VERSION 5.7 ;
  NOWIREEXTENSIONATPIN ON ;
  DIVIDERCHAR "/" ;
  BUSBITCHARS "[]" ;
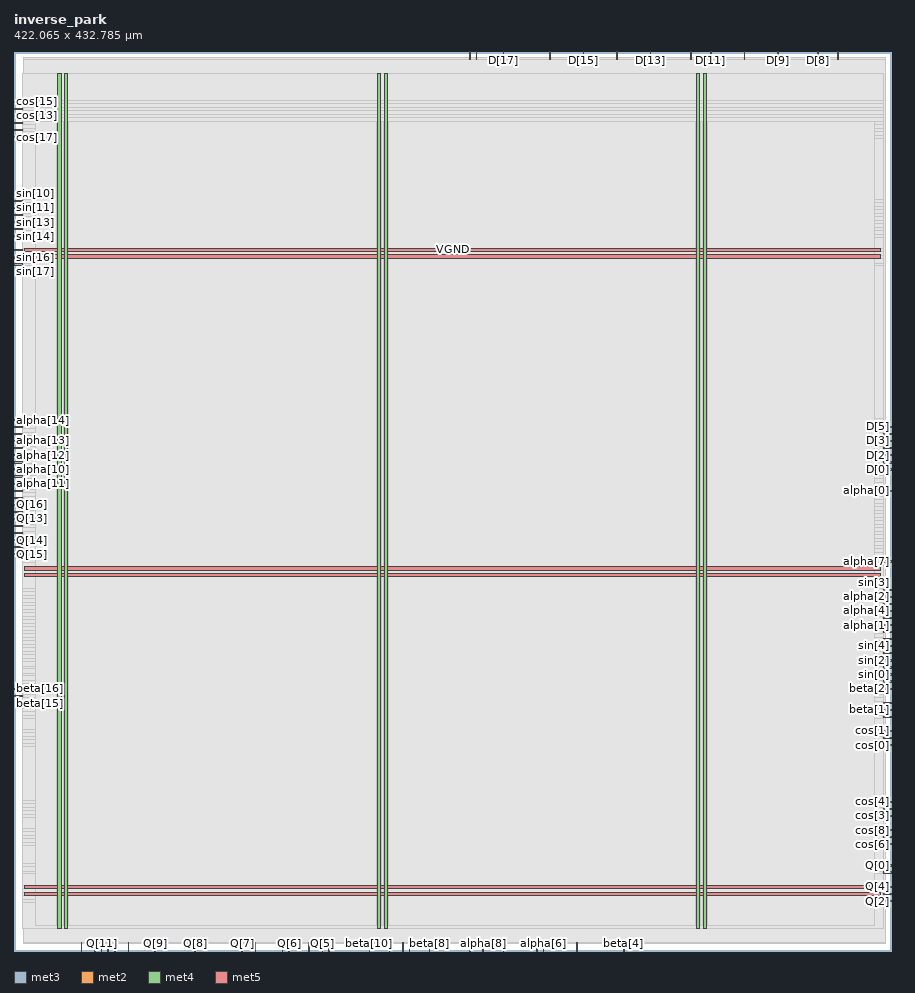
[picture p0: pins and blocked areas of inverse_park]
MACRO inverse_park
  CLASS BLOCK ;
  FOREIGN inverse_park ;
  ORIGIN 0.000 0.000 ;
  SIZE 422.065 BY 432.785 ;
  PIN D[0]
    DIRECTION INPUT ;
    USE SIGNAL ;
    ANTENNAGATEAREA 0.196500 ;
    PORT
      LAYER met3 ;
        RECT 418.065 231.240 422.065 231.840 ;
    END
  END D[0]
  PIN D[10]
    DIRECTION INPUT ;
    USE SIGNAL ;
    ANTENNAGATEAREA 0.213000 ;
    PORT
      LAYER met2 ;
        RECT 351.070 428.785 351.350 432.785 ;
    END
  END D[10]
  PIN D[11]
    DIRECTION INPUT ;
    USE SIGNAL ;
    ANTENNAGATEAREA 0.196500 ;
    PORT
      LAYER met2 ;
        RECT 334.970 428.785 335.250 432.785 ;
    END
  END D[11]
  PIN D[12]
    DIRECTION INPUT ;
    USE SIGNAL ;
    ANTENNAGATEAREA 0.196500 ;
    PORT
      LAYER met2 ;
        RECT 325.310 428.785 325.590 432.785 ;
    END
  END D[12]
  PIN D[13]
    DIRECTION INPUT ;
    USE SIGNAL ;
    ANTENNAGATEAREA 0.196500 ;
    PORT
      LAYER met2 ;
        RECT 305.990 428.785 306.270 432.785 ;
    END
  END D[13]
  PIN D[14]
    DIRECTION INPUT ;
    USE SIGNAL ;
    ANTENNAGATEAREA 0.159000 ;
    PORT
      LAYER met2 ;
        RECT 289.890 428.785 290.170 432.785 ;
    END
  END D[14]
  PIN D[15]
    DIRECTION INPUT ;
    USE SIGNAL ;
    ANTENNAGATEAREA 0.196500 ;
    PORT
      LAYER met2 ;
        RECT 273.790 428.785 274.070 432.785 ;
    END
  END D[15]
  PIN D[16]
    DIRECTION INPUT ;
    USE SIGNAL ;
    ANTENNAGATEAREA 0.196500 ;
    PORT
      LAYER met2 ;
        RECT 257.690 428.785 257.970 432.785 ;
    END
  END D[16]
  PIN D[17]
    DIRECTION INPUT ;
    USE SIGNAL ;
    ANTENNAGATEAREA 0.213000 ;
    PORT
      LAYER met2 ;
        RECT 235.150 428.785 235.430 432.785 ;
    END
  END D[17]
  PIN D[18]
    DIRECTION INPUT ;
    USE SIGNAL ;
    ANTENNAGATEAREA 0.159000 ;
    PORT
      LAYER met2 ;
        RECT 219.050 428.785 219.330 432.785 ;
    END
  END D[18]
  PIN D[1]
    DIRECTION INPUT ;
    USE SIGNAL ;
    ANTENNAGATEAREA 0.159000 ;
    PORT
      LAYER met3 ;
        RECT 418.065 234.640 422.065 235.240 ;
    END
  END D[1]
  PIN D[2]
    DIRECTION INPUT ;
    USE SIGNAL ;
    ANTENNAGATEAREA 0.213000 ;
    PORT
      LAYER met3 ;
        RECT 418.065 238.040 422.065 238.640 ;
    END
  END D[2]
  PIN D[3]
    DIRECTION INPUT ;
    USE SIGNAL ;
    ANTENNAGATEAREA 0.159000 ;
    PORT
      LAYER met3 ;
        RECT 418.065 241.440 422.065 242.040 ;
    END
  END D[3]
  PIN D[4]
    DIRECTION INPUT ;
    USE SIGNAL ;
    ANTENNAGATEAREA 0.196500 ;
    PORT
      LAYER met3 ;
        RECT 418.065 244.840 422.065 245.440 ;
    END
  END D[4]
  PIN D[5]
    DIRECTION INPUT ;
    USE SIGNAL ;
    ANTENNAGATEAREA 0.213000 ;
    PORT
      LAYER met3 ;
        RECT 418.065 248.240 422.065 248.840 ;
    END
  END D[5]
  PIN D[6]
    DIRECTION INPUT ;
    USE SIGNAL ;
    ANTENNAGATEAREA 0.196500 ;
    PORT
      LAYER met3 ;
        RECT 418.065 251.640 422.065 252.240 ;
    END
  END D[6]
  PIN D[7]
    DIRECTION INPUT ;
    USE SIGNAL ;
    ANTENNAGATEAREA 0.159000 ;
    PORT
      LAYER met2 ;
        RECT 396.150 428.785 396.430 432.785 ;
    END
  END D[7]
  PIN D[8]
    DIRECTION INPUT ;
    USE SIGNAL ;
    ANTENNAGATEAREA 0.196500 ;
    PORT
      LAYER met2 ;
        RECT 386.490 428.785 386.770 432.785 ;
    END
  END D[8]
  PIN D[9]
    DIRECTION INPUT ;
    USE SIGNAL ;
    ANTENNAGATEAREA 0.213000 ;
    PORT
      LAYER met2 ;
        RECT 367.170 428.785 367.450 432.785 ;
    END
  END D[9]
  PIN Q[0]
    DIRECTION INPUT ;
    USE SIGNAL ;
    ANTENNAGATEAREA 0.213000 ;
    PORT
      LAYER met3 ;
        RECT 418.065 40.840 422.065 41.440 ;
    END
  END Q[0]
  PIN Q[10]
    DIRECTION INPUT ;
    USE SIGNAL ;
    ANTENNAGATEAREA 0.213000 ;
    PORT
      LAYER met2 ;
        RECT 54.830 0.000 55.110 4.000 ;
    END
  END Q[10]
  PIN Q[11]
    DIRECTION INPUT ;
    USE SIGNAL ;
    ANTENNAGATEAREA 0.196500 ;
    PORT
      LAYER met2 ;
        RECT 41.950 0.000 42.230 4.000 ;
    END
  END Q[11]
  PIN Q[12]
    DIRECTION INPUT ;
    USE SIGNAL ;
    ANTENNAGATEAREA 0.196500 ;
    PORT
      LAYER met2 ;
        RECT 32.290 0.000 32.570 4.000 ;
    END
  END Q[12]
  PIN Q[13]
    DIRECTION INPUT ;
    USE SIGNAL ;
    ANTENNAGATEAREA 0.196500 ;
    PORT
      LAYER met3 ;
        RECT 0.000 207.440 4.000 208.040 ;
    END
  END Q[13]
  PIN Q[14]
    DIRECTION INPUT ;
    USE SIGNAL ;
    ANTENNAGATEAREA 0.247500 ;
    PORT
      LAYER met3 ;
        RECT 0.000 197.240 4.000 197.840 ;
    END
  END Q[14]
  PIN Q[15]
    DIRECTION INPUT ;
    USE SIGNAL ;
    ANTENNAGATEAREA 0.495000 ;
    PORT
      LAYER met3 ;
        RECT 0.000 193.840 4.000 194.440 ;
    END
  END Q[15]
  PIN Q[16]
    DIRECTION INPUT ;
    USE SIGNAL ;
    ANTENNAGATEAREA 0.495000 ;
    PORT
      LAYER met3 ;
        RECT 0.000 210.840 4.000 211.440 ;
    END
  END Q[16]
  PIN Q[17]
    DIRECTION INPUT ;
    USE SIGNAL ;
    ANTENNAGATEAREA 0.196500 ;
    PORT
      LAYER met3 ;
        RECT 0.000 200.640 4.000 201.240 ;
    END
  END Q[17]
  PIN Q[18]
    DIRECTION INPUT ;
    USE SIGNAL ;
    ANTENNAGATEAREA 0.196500 ;
    PORT
      LAYER met3 ;
        RECT 0.000 214.240 4.000 214.840 ;
    END
  END Q[18]
  PIN Q[1]
    DIRECTION INPUT ;
    USE SIGNAL ;
    ANTENNAGATEAREA 0.196500 ;
    PORT
      LAYER met3 ;
        RECT 418.065 37.440 422.065 38.040 ;
    END
  END Q[1]
  PIN Q[2]
    DIRECTION INPUT ;
    USE SIGNAL ;
    ANTENNAGATEAREA 0.159000 ;
    PORT
      LAYER met3 ;
        RECT 418.065 27.240 422.065 27.840 ;
    END
  END Q[2]
  PIN Q[3]
    DIRECTION INPUT ;
    USE SIGNAL ;
    ANTENNAGATEAREA 0.213000 ;
    PORT
      LAYER met3 ;
        RECT 418.065 23.840 422.065 24.440 ;
    END
  END Q[3]
  PIN Q[4]
    DIRECTION INPUT ;
    USE SIGNAL ;
    ANTENNAGATEAREA 0.196500 ;
    PORT
      LAYER met3 ;
        RECT 418.065 30.640 422.065 31.240 ;
    END
  END Q[4]
  PIN Q[5]
    DIRECTION INPUT ;
    USE SIGNAL ;
    ANTENNAGATEAREA 0.196500 ;
    PORT
      LAYER met2 ;
        RECT 148.210 0.000 148.490 4.000 ;
    END
  END Q[5]
  PIN Q[6]
    DIRECTION INPUT ;
    USE SIGNAL ;
    ANTENNAGATEAREA 0.196500 ;
    PORT
      LAYER met2 ;
        RECT 132.110 0.000 132.390 4.000 ;
    END
  END Q[6]
  PIN Q[7]
    DIRECTION INPUT ;
    USE SIGNAL ;
    ANTENNAGATEAREA 0.159000 ;
    PORT
      LAYER met2 ;
        RECT 109.570 0.000 109.850 4.000 ;
    END
  END Q[7]
  PIN Q[8]
    DIRECTION INPUT ;
    USE SIGNAL ;
    ANTENNAGATEAREA 0.196500 ;
    PORT
      LAYER met2 ;
        RECT 87.030 0.000 87.310 4.000 ;
    END
  END Q[8]
  PIN Q[9]
    DIRECTION INPUT ;
    USE SIGNAL ;
    ANTENNAGATEAREA 0.213000 ;
    PORT
      LAYER met2 ;
        RECT 67.710 0.000 67.990 4.000 ;
    END
  END Q[9]
  PIN VGND
    DIRECTION INOUT ;
    USE GROUND ;
    PORT
      LAYER met4 ;
        RECT 24.340 10.640 25.940 421.840 ;
    END
    PORT
      LAYER met4 ;
        RECT 177.940 10.640 179.540 421.840 ;
    END
    PORT
      LAYER met4 ;
        RECT 331.540 10.640 333.140 421.840 ;
    END
    PORT
      LAYER met5 ;
        RECT 5.280 30.030 416.540 31.630 ;
    END
    PORT
      LAYER met5 ;
        RECT 5.280 183.210 416.540 184.810 ;
    END
    PORT
      LAYER met5 ;
        RECT 5.280 336.390 416.540 337.990 ;
    END
  END VGND
  PIN VPWR
    DIRECTION INOUT ;
    USE POWER ;
    PORT
      LAYER met4 ;
        RECT 21.040 10.640 22.640 421.840 ;
    END
    PORT
      LAYER met4 ;
        RECT 174.640 10.640 176.240 421.840 ;
    END
    PORT
      LAYER met4 ;
        RECT 328.240 10.640 329.840 421.840 ;
    END
    PORT
      LAYER met5 ;
        RECT 5.280 26.730 416.540 28.330 ;
    END
    PORT
      LAYER met5 ;
        RECT 5.280 179.910 416.540 181.510 ;
    END
    PORT
      LAYER met5 ;
        RECT 5.280 333.090 416.540 334.690 ;
    END
  END VPWR
  PIN alpha[0]
    DIRECTION OUTPUT ;
    USE SIGNAL ;
    ANTENNADIFFAREA 0.445500 ;
    PORT
      LAYER met3 ;
        RECT 418.065 221.040 422.065 221.640 ;
    END
  END alpha[0]
  PIN alpha[10]
    DIRECTION OUTPUT ;
    USE SIGNAL ;
    ANTENNADIFFAREA 0.795200 ;
    PORT
      LAYER met3 ;
        RECT 0.000 231.240 4.000 231.840 ;
    END
  END alpha[10]
  PIN alpha[11]
    DIRECTION OUTPUT ;
    USE SIGNAL ;
    ANTENNADIFFAREA 0.795200 ;
    PORT
      LAYER met3 ;
        RECT 0.000 227.840 4.000 228.440 ;
    END
  END alpha[11]
  PIN alpha[12]
    DIRECTION OUTPUT ;
    USE SIGNAL ;
    ANTENNADIFFAREA 0.795200 ;
    PORT
      LAYER met3 ;
        RECT 0.000 238.040 4.000 238.640 ;
    END
  END alpha[12]
  PIN alpha[13]
    DIRECTION OUTPUT ;
    USE SIGNAL ;
    ANTENNADIFFAREA 0.795200 ;
    PORT
      LAYER met3 ;
        RECT 0.000 241.440 4.000 242.040 ;
    END
  END alpha[13]
  PIN alpha[14]
    DIRECTION OUTPUT ;
    USE SIGNAL ;
    ANTENNADIFFAREA 0.795200 ;
    PORT
      LAYER met3 ;
        RECT 0.000 255.040 4.000 255.640 ;
    END
  END alpha[14]
  PIN alpha[15]
    DIRECTION OUTPUT ;
    USE SIGNAL ;
    ANTENNADIFFAREA 0.795200 ;
    PORT
      LAYER met3 ;
        RECT 0.000 244.840 4.000 245.440 ;
    END
  END alpha[15]
  PIN alpha[16]
    DIRECTION OUTPUT ;
    USE SIGNAL ;
    ANTENNADIFFAREA 0.795200 ;
    PORT
      LAYER met3 ;
        RECT 0.000 251.640 4.000 252.240 ;
    END
  END alpha[16]
  PIN alpha[17]
    DIRECTION OUTPUT ;
    USE SIGNAL ;
    ANTENNADIFFAREA 0.795200 ;
    PORT
      LAYER met3 ;
        RECT 0.000 234.640 4.000 235.240 ;
    END
  END alpha[17]
  PIN alpha[18]
    DIRECTION OUTPUT ;
    USE SIGNAL ;
    ANTENNADIFFAREA 0.795200 ;
    PORT
      LAYER met3 ;
        RECT 0.000 248.240 4.000 248.840 ;
    END
  END alpha[18]
  PIN alpha[1]
    DIRECTION OUTPUT ;
    USE SIGNAL ;
    ANTENNADIFFAREA 0.795200 ;
    PORT
      LAYER met3 ;
        RECT 418.065 156.440 422.065 157.040 ;
    END
  END alpha[1]
  PIN alpha[2]
    DIRECTION OUTPUT ;
    USE SIGNAL ;
    ANTENNADIFFAREA 0.795200 ;
    PORT
      LAYER met3 ;
        RECT 418.065 170.040 422.065 170.640 ;
    END
  END alpha[2]
  PIN alpha[3]
    DIRECTION OUTPUT ;
    USE SIGNAL ;
    ANTENNADIFFAREA 0.795200 ;
    PORT
      LAYER met3 ;
        RECT 418.065 159.840 422.065 160.440 ;
    END
  END alpha[3]
  PIN alpha[4]
    DIRECTION OUTPUT ;
    USE SIGNAL ;
    ANTENNADIFFAREA 0.445500 ;
    PORT
      LAYER met3 ;
        RECT 418.065 163.240 422.065 163.840 ;
    END
  END alpha[4]
  PIN alpha[5]
    DIRECTION OUTPUT ;
    USE SIGNAL ;
    ANTENNADIFFAREA 0.795200 ;
    PORT
      LAYER met3 ;
        RECT 418.065 166.640 422.065 167.240 ;
    END
  END alpha[5]
  PIN alpha[6]
    DIRECTION OUTPUT ;
    USE SIGNAL ;
    ANTENNADIFFAREA 0.795200 ;
    PORT
      LAYER met2 ;
        RECT 254.470 0.000 254.750 4.000 ;
    END
  END alpha[6]
  PIN alpha[7]
    DIRECTION OUTPUT ;
    USE SIGNAL ;
    ANTENNADIFFAREA 0.795200 ;
    PORT
      LAYER met3 ;
        RECT 418.065 187.040 422.065 187.640 ;
    END
  END alpha[7]
  PIN alpha[8]
    DIRECTION OUTPUT ;
    USE SIGNAL ;
    ANTENNADIFFAREA 0.795200 ;
    PORT
      LAYER met2 ;
        RECT 225.490 0.000 225.770 4.000 ;
    END
  END alpha[8]
  PIN alpha[9]
    DIRECTION OUTPUT ;
    USE SIGNAL ;
    ANTENNADIFFAREA 0.795200 ;
    PORT
      LAYER met3 ;
        RECT 0.000 221.040 4.000 221.640 ;
    END
  END alpha[9]
  PIN beta[0]
    DIRECTION OUTPUT ;
    USE SIGNAL ;
    ANTENNADIFFAREA 0.795200 ;
    PORT
      LAYER met3 ;
        RECT 418.065 112.240 422.065 112.840 ;
    END
  END beta[0]
  PIN beta[10]
    DIRECTION OUTPUT ;
    USE SIGNAL ;
    ANTENNADIFFAREA 0.795200 ;
    PORT
      LAYER met2 ;
        RECT 170.750 0.000 171.030 4.000 ;
    END
  END beta[10]
  PIN beta[11]
    DIRECTION OUTPUT ;
    USE SIGNAL ;
    ANTENNADIFFAREA 0.795200 ;
    PORT
      LAYER met2 ;
        RECT 151.430 0.000 151.710 4.000 ;
    END
  END beta[11]
  PIN beta[12]
    DIRECTION OUTPUT ;
    USE SIGNAL ;
    ANTENNADIFFAREA 0.795200 ;
    PORT
      LAYER met2 ;
        RECT 141.770 0.000 142.050 4.000 ;
    END
  END beta[12]
  PIN beta[13]
    DIRECTION OUTPUT ;
    USE SIGNAL ;
    ANTENNADIFFAREA 0.795200 ;
    PORT
      LAYER met2 ;
        RECT 128.890 0.000 129.170 4.000 ;
    END
  END beta[13]
  PIN beta[14]
    DIRECTION OUTPUT ;
    USE SIGNAL ;
    ANTENNADIFFAREA 0.795200 ;
    PORT
      LAYER met2 ;
        RECT 116.010 0.000 116.290 4.000 ;
    END
  END beta[14]
  PIN beta[15]
    DIRECTION OUTPUT ;
    USE SIGNAL ;
    ANTENNADIFFAREA 0.795200 ;
    PORT
      LAYER met3 ;
        RECT 0.000 122.440 4.000 123.040 ;
    END
  END beta[15]
  PIN beta[16]
    DIRECTION OUTPUT ;
    USE SIGNAL ;
    ANTENNADIFFAREA 0.795200 ;
    PORT
      LAYER met3 ;
        RECT 0.000 125.840 4.000 126.440 ;
    END
  END beta[16]
  PIN beta[17]
    DIRECTION OUTPUT ;
    USE SIGNAL ;
    ANTENNADIFFAREA 0.795200 ;
    PORT
      LAYER met3 ;
        RECT 0.000 217.640 4.000 218.240 ;
    END
  END beta[17]
  PIN beta[18]
    DIRECTION OUTPUT ;
    USE SIGNAL ;
    ANTENNADIFFAREA 0.795200 ;
    PORT
      LAYER met3 ;
        RECT 0.000 224.440 4.000 225.040 ;
    END
  END beta[18]
  PIN beta[1]
    DIRECTION OUTPUT ;
    USE SIGNAL ;
    ANTENNADIFFAREA 0.795200 ;
    PORT
      LAYER met3 ;
        RECT 418.065 115.640 422.065 116.240 ;
    END
  END beta[1]
  PIN beta[2]
    DIRECTION OUTPUT ;
    USE SIGNAL ;
    ANTENNADIFFAREA 0.445500 ;
    PORT
      LAYER met3 ;
        RECT 418.065 125.840 422.065 126.440 ;
    END
  END beta[2]
  PIN beta[3]
    DIRECTION OUTPUT ;
    USE SIGNAL ;
    ANTENNADIFFAREA 0.795200 ;
    PORT
      LAYER met3 ;
        RECT 418.065 119.040 422.065 119.640 ;
    END
  END beta[3]
  PIN beta[4]
    DIRECTION OUTPUT ;
    USE SIGNAL ;
    ANTENNADIFFAREA 0.795200 ;
    PORT
      LAYER met2 ;
        RECT 293.110 0.000 293.390 4.000 ;
    END
  END beta[4]
  PIN beta[5]
    DIRECTION OUTPUT ;
    USE SIGNAL ;
    ANTENNADIFFAREA 0.795200 ;
    PORT
      LAYER met2 ;
        RECT 270.570 0.000 270.850 4.000 ;
    END
  END beta[5]
  PIN beta[6]
    DIRECTION OUTPUT ;
    USE SIGNAL ;
    ANTENNADIFFAREA 0.795200 ;
    PORT
      LAYER met2 ;
        RECT 251.250 0.000 251.530 4.000 ;
    END
  END beta[6]
  PIN beta[7]
    DIRECTION OUTPUT ;
    USE SIGNAL ;
    ANTENNADIFFAREA 0.795200 ;
    PORT
      LAYER met2 ;
        RECT 235.150 0.000 235.430 4.000 ;
    END
  END beta[7]
  PIN beta[8]
    DIRECTION OUTPUT ;
    USE SIGNAL ;
    ANTENNADIFFAREA 0.795200 ;
    PORT
      LAYER met2 ;
        RECT 199.730 0.000 200.010 4.000 ;
    END
  END beta[8]
  PIN beta[9]
    DIRECTION OUTPUT ;
    USE SIGNAL ;
    ANTENNADIFFAREA 0.795200 ;
    PORT
      LAYER met2 ;
        RECT 180.410 0.000 180.690 4.000 ;
    END
  END beta[9]
  PIN clk
    DIRECTION INPUT ;
    USE SIGNAL ;
    ANTENNAGATEAREA 0.852000 ;
    PORT
      LAYER met3 ;
        RECT 0.000 190.440 4.000 191.040 ;
    END
  END clk
  PIN cos[0]
    DIRECTION INPUT ;
    USE SIGNAL ;
    ANTENNAGATEAREA 0.247500 ;
    PORT
      LAYER met3 ;
        RECT 418.065 98.640 422.065 99.240 ;
    END
  END cos[0]
  PIN cos[10]
    DIRECTION INPUT ;
    USE SIGNAL ;
    ANTENNAGATEAREA 0.213000 ;
    PORT
      LAYER met2 ;
        RECT 45.170 0.000 45.450 4.000 ;
    END
  END cos[10]
  PIN cos[11]
    DIRECTION INPUT ;
    USE SIGNAL ;
    ANTENNAGATEAREA 0.159000 ;
    PORT
      LAYER met2 ;
        RECT 38.730 0.000 39.010 4.000 ;
    END
  END cos[11]
  PIN cos[12]
    DIRECTION INPUT ;
    USE SIGNAL ;
    ANTENNAGATEAREA 0.159000 ;
    PORT
      LAYER met3 ;
        RECT 0.000 404.640 4.000 405.240 ;
    END
  END cos[12]
  PIN cos[13]
    DIRECTION INPUT ;
    USE SIGNAL ;
    ANTENNAGATEAREA 0.126000 ;
    PORT
      LAYER met3 ;
        RECT 0.000 401.240 4.000 401.840 ;
    END
  END cos[13]
  PIN cos[14]
    DIRECTION INPUT ;
    USE SIGNAL ;
    ANTENNAGATEAREA 0.213000 ;
    PORT
      LAYER met3 ;
        RECT 0.000 397.840 4.000 398.440 ;
    END
  END cos[14]
  PIN cos[15]
    DIRECTION INPUT ;
    USE SIGNAL ;
    ANTENNAGATEAREA 0.196500 ;
    PORT
      LAYER met3 ;
        RECT 0.000 408.040 4.000 408.640 ;
    END
  END cos[15]
  PIN cos[16]
    DIRECTION INPUT ;
    USE SIGNAL ;
    ANTENNAGATEAREA 0.196500 ;
    PORT
      LAYER met3 ;
        RECT 0.000 394.440 4.000 395.040 ;
    END
  END cos[16]
  PIN cos[17]
    DIRECTION INPUT ;
    USE SIGNAL ;
    ANTENNAGATEAREA 0.196500 ;
    PORT
      LAYER met3 ;
        RECT 0.000 391.040 4.000 391.640 ;
    END
  END cos[17]
  PIN cos[18]
    DIRECTION INPUT ;
    USE SIGNAL ;
    ANTENNAGATEAREA 0.213000 ;
    PORT
      LAYER met2 ;
        RECT 186.850 0.000 187.130 4.000 ;
    END
  END cos[18]
  PIN cos[1]
    DIRECTION INPUT ;
    USE SIGNAL ;
    ANTENNAGATEAREA 0.742500 ;
    PORT
      LAYER met3 ;
        RECT 418.065 102.040 422.065 102.640 ;
    END
  END cos[1]
  PIN cos[2]
    DIRECTION INPUT ;
    USE SIGNAL ;
    ANTENNAGATEAREA 0.196500 ;
    PORT
      LAYER met3 ;
        RECT 418.065 105.440 422.065 106.040 ;
    END
  END cos[2]
  PIN cos[3]
    DIRECTION INPUT ;
    USE SIGNAL ;
    ANTENNAGATEAREA 0.213000 ;
    PORT
      LAYER met3 ;
        RECT 418.065 64.640 422.065 65.240 ;
    END
  END cos[3]
  PIN cos[4]
    DIRECTION INPUT ;
    USE SIGNAL ;
    ANTENNAGATEAREA 0.213000 ;
    PORT
      LAYER met3 ;
        RECT 418.065 68.040 422.065 68.640 ;
    END
  END cos[4]
  PIN cos[5]
    DIRECTION INPUT ;
    USE SIGNAL ;
    ANTENNAGATEAREA 0.196500 ;
    PORT
      LAYER met3 ;
        RECT 418.065 71.440 422.065 72.040 ;
    END
  END cos[5]
  PIN cos[6]
    DIRECTION INPUT ;
    USE SIGNAL ;
    ANTENNAGATEAREA 0.196500 ;
    PORT
      LAYER met3 ;
        RECT 418.065 51.040 422.065 51.640 ;
    END
  END cos[6]
  PIN cos[7]
    DIRECTION INPUT ;
    USE SIGNAL ;
    ANTENNAGATEAREA 0.196500 ;
    PORT
      LAYER met3 ;
        RECT 418.065 54.440 422.065 55.040 ;
    END
  END cos[7]
  PIN cos[8]
    DIRECTION INPUT ;
    USE SIGNAL ;
    ANTENNAGATEAREA 0.247500 ;
    PORT
      LAYER met3 ;
        RECT 418.065 57.840 422.065 58.440 ;
    END
  END cos[8]
  PIN cos[9]
    DIRECTION INPUT ;
    USE SIGNAL ;
    ANTENNAGATEAREA 0.247500 ;
    PORT
      LAYER met2 ;
        RECT 48.390 0.000 48.670 4.000 ;
    END
  END cos[9]
  PIN done
    DIRECTION OUTPUT ;
    USE SIGNAL ;
    ANTENNADIFFAREA 0.795200 ;
    PORT
      LAYER met2 ;
        RECT 190.070 0.000 190.350 4.000 ;
    END
  END done
  PIN rstb
    DIRECTION INPUT ;
    USE SIGNAL ;
    ANTENNAGATEAREA 0.159000 ;
    PORT
      LAYER met3 ;
        RECT 0.000 204.040 4.000 204.640 ;
    END
  END rstb
  PIN sin[0]
    DIRECTION INPUT ;
    USE SIGNAL ;
    ANTENNAGATEAREA 0.247500 ;
    PORT
      LAYER met3 ;
        RECT 418.065 129.240 422.065 129.840 ;
    END
  END sin[0]
  PIN sin[10]
    DIRECTION INPUT ;
    USE SIGNAL ;
    ANTENNAGATEAREA 0.247500 ;
    PORT
      LAYER met3 ;
        RECT 0.000 360.440 4.000 361.040 ;
    END
  END sin[10]
  PIN sin[11]
    DIRECTION INPUT ;
    USE SIGNAL ;
    ANTENNAGATEAREA 0.213000 ;
    PORT
      LAYER met3 ;
        RECT 0.000 357.040 4.000 357.640 ;
    END
  END sin[11]
  PIN sin[12]
    DIRECTION INPUT ;
    USE SIGNAL ;
    ANTENNAGATEAREA 0.247500 ;
    PORT
      LAYER met3 ;
        RECT 0.000 353.640 4.000 354.240 ;
    END
  END sin[12]
  PIN sin[13]
    DIRECTION INPUT ;
    USE SIGNAL ;
    ANTENNAGATEAREA 0.213000 ;
    PORT
      LAYER met3 ;
        RECT 0.000 350.240 4.000 350.840 ;
    END
  END sin[13]
  PIN sin[14]
    DIRECTION INPUT ;
    USE SIGNAL ;
    ANTENNAGATEAREA 0.213000 ;
    PORT
      LAYER met3 ;
        RECT 0.000 346.840 4.000 347.440 ;
    END
  END sin[14]
  PIN sin[15]
    DIRECTION INPUT ;
    USE SIGNAL ;
    ANTENNAGATEAREA 0.196500 ;
    PORT
      LAYER met3 ;
        RECT 0.000 336.640 4.000 337.240 ;
    END
  END sin[15]
  PIN sin[16]
    DIRECTION INPUT ;
    USE SIGNAL ;
    ANTENNAGATEAREA 0.196500 ;
    PORT
      LAYER met3 ;
        RECT 0.000 333.240 4.000 333.840 ;
    END
  END sin[16]
  PIN sin[17]
    DIRECTION INPUT ;
    USE SIGNAL ;
    ANTENNAGATEAREA 0.213000 ;
    PORT
      LAYER met3 ;
        RECT 0.000 329.840 4.000 330.440 ;
    END
  END sin[17]
  PIN sin[18]
    DIRECTION INPUT ;
    USE SIGNAL ;
    ANTENNAGATEAREA 0.213000 ;
    PORT
      LAYER met2 ;
        RECT 222.270 428.785 222.550 432.785 ;
    END
  END sin[18]
  PIN sin[1]
    DIRECTION INPUT ;
    USE SIGNAL ;
    ANTENNAGATEAREA 0.247500 ;
    PORT
      LAYER met3 ;
        RECT 418.065 132.640 422.065 133.240 ;
    END
  END sin[1]
  PIN sin[2]
    DIRECTION INPUT ;
    USE SIGNAL ;
    ANTENNAGATEAREA 0.213000 ;
    PORT
      LAYER met3 ;
        RECT 418.065 136.040 422.065 136.640 ;
    END
  END sin[2]
  PIN sin[3]
    DIRECTION INPUT ;
    USE SIGNAL ;
    ANTENNAGATEAREA 0.196500 ;
    PORT
      LAYER met3 ;
        RECT 418.065 173.440 422.065 174.040 ;
    END
  END sin[3]
  PIN sin[4]
    DIRECTION INPUT ;
    USE SIGNAL ;
    ANTENNAGATEAREA 0.196500 ;
    PORT
      LAYER met3 ;
        RECT 418.065 142.840 422.065 143.440 ;
    END
  END sin[4]
  PIN sin[5]
    DIRECTION INPUT ;
    USE SIGNAL ;
    ANTENNAGATEAREA 0.213000 ;
    PORT
      LAYER met3 ;
        RECT 418.065 139.440 422.065 140.040 ;
    END
  END sin[5]
  PIN sin[6]
    DIRECTION INPUT ;
    USE SIGNAL ;
    ANTENNAGATEAREA 0.196500 ;
    PORT
      LAYER met3 ;
        RECT 418.065 149.640 422.065 150.240 ;
    END
  END sin[6]
  PIN sin[7]
    DIRECTION INPUT ;
    USE SIGNAL ;
    ANTENNAGATEAREA 0.213000 ;
    PORT
      LAYER met3 ;
        RECT 418.065 153.040 422.065 153.640 ;
    END
  END sin[7]
  PIN sin[8]
    DIRECTION INPUT ;
    USE SIGNAL ;
    ANTENNAGATEAREA 0.213000 ;
    PORT
      LAYER met3 ;
        RECT 418.065 146.240 422.065 146.840 ;
    END
  END sin[8]
  PIN sin[9]
    DIRECTION INPUT ;
    USE SIGNAL ;
    ANTENNAGATEAREA 0.213000 ;
    PORT
      LAYER met3 ;
        RECT 0.000 343.440 4.000 344.040 ;
    END
  END sin[9]
  PIN start
    DIRECTION INPUT ;
    USE SIGNAL ;
    ANTENNAGATEAREA 0.196500 ;
    PORT
      LAYER met2 ;
        RECT 219.050 0.000 219.330 4.000 ;
    END
  END start
  OBS
      LAYER li1 ;
        RECT 5.520 10.795 416.300 421.685 ;
      LAYER met1 ;
        RECT 4.670 10.640 418.990 421.840 ;
      LAYER met2 ;
        RECT 4.690 428.505 218.770 429.490 ;
        RECT 219.610 428.505 221.990 429.490 ;
        RECT 222.830 428.505 234.870 429.490 ;
        RECT 235.710 428.505 257.410 429.490 ;
        RECT 258.250 428.505 273.510 429.490 ;
        RECT 274.350 428.505 289.610 429.490 ;
        RECT 290.450 428.505 305.710 429.490 ;
        RECT 306.550 428.505 325.030 429.490 ;
        RECT 325.870 428.505 334.690 429.490 ;
        RECT 335.530 428.505 350.790 429.490 ;
        RECT 351.630 428.505 366.890 429.490 ;
        RECT 367.730 428.505 386.210 429.490 ;
        RECT 387.050 428.505 395.870 429.490 ;
        RECT 396.710 428.505 418.960 429.490 ;
        RECT 4.690 4.280 418.960 428.505 ;
        RECT 4.690 3.670 32.010 4.280 ;
        RECT 32.850 3.670 38.450 4.280 ;
        RECT 39.290 3.670 41.670 4.280 ;
        RECT 42.510 3.670 44.890 4.280 ;
        RECT 45.730 3.670 48.110 4.280 ;
        RECT 48.950 3.670 54.550 4.280 ;
        RECT 55.390 3.670 67.430 4.280 ;
        RECT 68.270 3.670 86.750 4.280 ;
        RECT 87.590 3.670 109.290 4.280 ;
        RECT 110.130 3.670 115.730 4.280 ;
        RECT 116.570 3.670 128.610 4.280 ;
        RECT 129.450 3.670 131.830 4.280 ;
        RECT 132.670 3.670 141.490 4.280 ;
        RECT 142.330 3.670 147.930 4.280 ;
        RECT 148.770 3.670 151.150 4.280 ;
        RECT 151.990 3.670 170.470 4.280 ;
        RECT 171.310 3.670 180.130 4.280 ;
        RECT 180.970 3.670 186.570 4.280 ;
        RECT 187.410 3.670 189.790 4.280 ;
        RECT 190.630 3.670 199.450 4.280 ;
        RECT 200.290 3.670 218.770 4.280 ;
        RECT 219.610 3.670 225.210 4.280 ;
        RECT 226.050 3.670 234.870 4.280 ;
        RECT 235.710 3.670 250.970 4.280 ;
        RECT 251.810 3.670 254.190 4.280 ;
        RECT 255.030 3.670 270.290 4.280 ;
        RECT 271.130 3.670 292.830 4.280 ;
        RECT 293.670 3.670 418.960 4.280 ;
      LAYER met3 ;
        RECT 3.990 409.040 418.065 421.765 ;
        RECT 4.400 407.640 418.065 409.040 ;
        RECT 3.990 405.640 418.065 407.640 ;
        RECT 4.400 404.240 418.065 405.640 ;
        RECT 3.990 402.240 418.065 404.240 ;
        RECT 4.400 400.840 418.065 402.240 ;
        RECT 3.990 398.840 418.065 400.840 ;
        RECT 4.400 397.440 418.065 398.840 ;
        RECT 3.990 395.440 418.065 397.440 ;
        RECT 4.400 394.040 418.065 395.440 ;
        RECT 3.990 392.040 418.065 394.040 ;
        RECT 4.400 390.640 418.065 392.040 ;
        RECT 3.990 361.440 418.065 390.640 ;
        RECT 4.400 360.040 418.065 361.440 ;
        RECT 3.990 358.040 418.065 360.040 ;
        RECT 4.400 356.640 418.065 358.040 ;
        RECT 3.990 354.640 418.065 356.640 ;
        RECT 4.400 353.240 418.065 354.640 ;
        RECT 3.990 351.240 418.065 353.240 ;
        RECT 4.400 349.840 418.065 351.240 ;
        RECT 3.990 347.840 418.065 349.840 ;
        RECT 4.400 346.440 418.065 347.840 ;
        RECT 3.990 344.440 418.065 346.440 ;
        RECT 4.400 343.040 418.065 344.440 ;
        RECT 3.990 337.640 418.065 343.040 ;
        RECT 4.400 336.240 418.065 337.640 ;
        RECT 3.990 334.240 418.065 336.240 ;
        RECT 4.400 332.840 418.065 334.240 ;
        RECT 3.990 330.840 418.065 332.840 ;
        RECT 4.400 329.440 418.065 330.840 ;
        RECT 3.990 256.040 418.065 329.440 ;
        RECT 4.400 254.640 418.065 256.040 ;
        RECT 3.990 252.640 418.065 254.640 ;
        RECT 4.400 251.240 417.665 252.640 ;
        RECT 3.990 249.240 418.065 251.240 ;
        RECT 4.400 247.840 417.665 249.240 ;
        RECT 3.990 245.840 418.065 247.840 ;
        RECT 4.400 244.440 417.665 245.840 ;
        RECT 3.990 242.440 418.065 244.440 ;
        RECT 4.400 241.040 417.665 242.440 ;
        RECT 3.990 239.040 418.065 241.040 ;
        RECT 4.400 237.640 417.665 239.040 ;
        RECT 3.990 235.640 418.065 237.640 ;
        RECT 4.400 234.240 417.665 235.640 ;
        RECT 3.990 232.240 418.065 234.240 ;
        RECT 4.400 230.840 417.665 232.240 ;
        RECT 3.990 228.840 418.065 230.840 ;
        RECT 4.400 227.440 418.065 228.840 ;
        RECT 3.990 225.440 418.065 227.440 ;
        RECT 4.400 224.040 418.065 225.440 ;
        RECT 3.990 222.040 418.065 224.040 ;
        RECT 4.400 220.640 417.665 222.040 ;
        RECT 3.990 218.640 418.065 220.640 ;
        RECT 4.400 217.240 418.065 218.640 ;
        RECT 3.990 215.240 418.065 217.240 ;
        RECT 4.400 213.840 418.065 215.240 ;
        RECT 3.990 211.840 418.065 213.840 ;
        RECT 4.400 210.440 418.065 211.840 ;
        RECT 3.990 208.440 418.065 210.440 ;
        RECT 4.400 207.040 418.065 208.440 ;
        RECT 3.990 205.040 418.065 207.040 ;
        RECT 4.400 203.640 418.065 205.040 ;
        RECT 3.990 201.640 418.065 203.640 ;
        RECT 4.400 200.240 418.065 201.640 ;
        RECT 3.990 198.240 418.065 200.240 ;
        RECT 4.400 196.840 418.065 198.240 ;
        RECT 3.990 194.840 418.065 196.840 ;
        RECT 4.400 193.440 418.065 194.840 ;
        RECT 3.990 191.440 418.065 193.440 ;
        RECT 4.400 190.040 418.065 191.440 ;
        RECT 3.990 188.040 418.065 190.040 ;
        RECT 3.990 186.640 417.665 188.040 ;
        RECT 3.990 174.440 418.065 186.640 ;
        RECT 3.990 173.040 417.665 174.440 ;
        RECT 3.990 171.040 418.065 173.040 ;
        RECT 3.990 169.640 417.665 171.040 ;
        RECT 3.990 167.640 418.065 169.640 ;
        RECT 3.990 166.240 417.665 167.640 ;
        RECT 3.990 164.240 418.065 166.240 ;
        RECT 3.990 162.840 417.665 164.240 ;
        RECT 3.990 160.840 418.065 162.840 ;
        RECT 3.990 159.440 417.665 160.840 ;
        RECT 3.990 157.440 418.065 159.440 ;
        RECT 3.990 156.040 417.665 157.440 ;
        RECT 3.990 154.040 418.065 156.040 ;
        RECT 3.990 152.640 417.665 154.040 ;
        RECT 3.990 150.640 418.065 152.640 ;
        RECT 3.990 149.240 417.665 150.640 ;
        RECT 3.990 147.240 418.065 149.240 ;
        RECT 3.990 145.840 417.665 147.240 ;
        RECT 3.990 143.840 418.065 145.840 ;
        RECT 3.990 142.440 417.665 143.840 ;
        RECT 3.990 140.440 418.065 142.440 ;
        RECT 3.990 139.040 417.665 140.440 ;
        RECT 3.990 137.040 418.065 139.040 ;
        RECT 3.990 135.640 417.665 137.040 ;
        RECT 3.990 133.640 418.065 135.640 ;
        RECT 3.990 132.240 417.665 133.640 ;
        RECT 3.990 130.240 418.065 132.240 ;
        RECT 3.990 128.840 417.665 130.240 ;
        RECT 3.990 126.840 418.065 128.840 ;
        RECT 4.400 125.440 417.665 126.840 ;
        RECT 3.990 123.440 418.065 125.440 ;
        RECT 4.400 122.040 418.065 123.440 ;
        RECT 3.990 120.040 418.065 122.040 ;
        RECT 3.990 118.640 417.665 120.040 ;
        RECT 3.990 116.640 418.065 118.640 ;
        RECT 3.990 115.240 417.665 116.640 ;
        RECT 3.990 113.240 418.065 115.240 ;
        RECT 3.990 111.840 417.665 113.240 ;
        RECT 3.990 106.440 418.065 111.840 ;
        RECT 3.990 105.040 417.665 106.440 ;
        RECT 3.990 103.040 418.065 105.040 ;
        RECT 3.990 101.640 417.665 103.040 ;
        RECT 3.990 99.640 418.065 101.640 ;
        RECT 3.990 98.240 417.665 99.640 ;
        RECT 3.990 72.440 418.065 98.240 ;
        RECT 3.990 71.040 417.665 72.440 ;
        RECT 3.990 69.040 418.065 71.040 ;
        RECT 3.990 67.640 417.665 69.040 ;
        RECT 3.990 65.640 418.065 67.640 ;
        RECT 3.990 64.240 417.665 65.640 ;
        RECT 3.990 58.840 418.065 64.240 ;
        RECT 3.990 57.440 417.665 58.840 ;
        RECT 3.990 55.440 418.065 57.440 ;
        RECT 3.990 54.040 417.665 55.440 ;
        RECT 3.990 52.040 418.065 54.040 ;
        RECT 3.990 50.640 417.665 52.040 ;
        RECT 3.990 41.840 418.065 50.640 ;
        RECT 3.990 40.440 417.665 41.840 ;
        RECT 3.990 38.440 418.065 40.440 ;
        RECT 3.990 37.040 417.665 38.440 ;
        RECT 3.990 31.640 418.065 37.040 ;
        RECT 3.990 30.240 417.665 31.640 ;
        RECT 3.990 28.240 418.065 30.240 ;
        RECT 3.990 26.840 417.665 28.240 ;
        RECT 3.990 24.840 418.065 26.840 ;
        RECT 3.990 23.440 417.665 24.840 ;
        RECT 3.990 10.715 418.065 23.440 ;
      LAYER met4 ;
        RECT 10.415 12.415 20.640 398.985 ;
        RECT 23.040 12.415 23.940 398.985 ;
        RECT 26.340 12.415 174.240 398.985 ;
        RECT 176.640 12.415 177.540 398.985 ;
        RECT 179.940 12.415 327.840 398.985 ;
        RECT 330.240 12.415 331.140 398.985 ;
        RECT 333.540 12.415 413.705 398.985 ;
  END
END inverse_park
END LIBRARY

